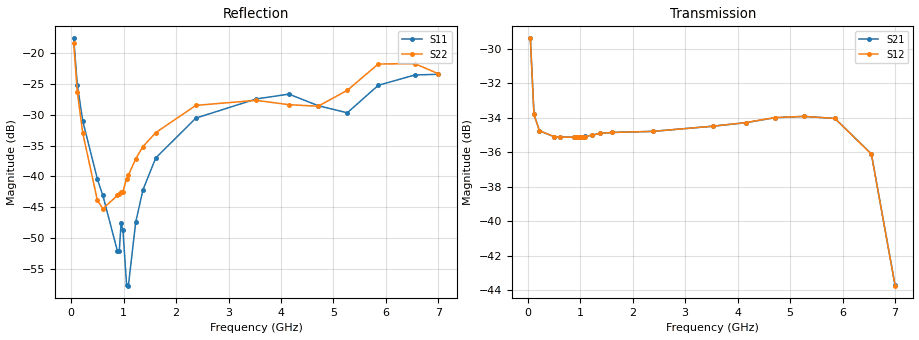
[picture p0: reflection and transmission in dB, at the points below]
! Integrated Device Technology
! Corporate Headquarters
! 6024 Silver Creek Valley Road
! San Jose, CA 95138  USA
! Phone:  1-408-284-8200
! Toll Free:  1-800-223-1366
! Webpage:  http://www.idt.com/
! Timing and RF Division
! 515 Groton Road, Suite 102
! Westford, MA 01886-6024
! Device:  F2258
! Description: Voltage Variable RF Attenuator
! Frequency:  50.0 -  6000.00 MHz
! Package:  3x3 mm Thin QFN Plastic Package: 16 pin
! Ports:  2 RF, 2 DC
!  Pin  1  = NC
!  Pin  2  = NC
!  Pin  3  = RF2  = Port 2
!  Pin  4  = GND
!  Pin  5  = Vdd
!  Pin  6  = NC
!  Pin  7  = VCTRL
!  Pin  8  = NC
!  Pin  9  = GND
!  Pin 10  = RF1  = Port 1
!  Pin 11  = NC
!  Pin 12  = NC
!  Pin 13  = NC
!  Pin 14  = NC
!  Pin 15  = NC
!  Pin 16  = NC
! Vcntrl:  2.050 Volts
! Vdd:  +3.300 Volts
! Current:  1.154 mA
! Data:  The device was measured on a the F2258 evaluation board which has
!  individual transmission lines to the RF pins.  Data was collected
!  using a calibrated network analyzer.  The evaluation board was
!  de-embedded using a TRL calibration technique.
!  The reference plane is the edge of the package pin.
! Misc:  SN 10
!  Action Tracker AT0285
! Date Measured:  2014-12-10
! Date:  2016-01-13  MJV
! Note:
!  Integrated Device Technology supplies this data as a sample of measured
!  data at the package pin for this product.  Your particular data for this
!  product may vary.
!  Data was taken at 25 degrees C.
!  Integrated Device Technology reserves the right to change this data at anytime.
!Freq_(GHz)  S11M_(dB)  S11P_(deg)  S21M_(dB)  S21P_(deg)  S12M_(dB)  S12P_(deg)  S22M_(dB)  S22P_(deg)
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# GHz S dB R 50
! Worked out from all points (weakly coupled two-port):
!   201 points, 50 MHz to 7 GHz, reference 50 ohm
!   highest |S21| = -29.40 dB at 50 MHz (marker M1); lowest = -43.7 dB at 7 GHz (marker M2)
!   lowest |S11| = -57.8 dB at 1.093 GHz (marker M3), VSWR 1.00, Z = 49.9 + j0.113 ohm
!   |S11| at or under -10 dB: start of sweep to end of sweep
!   |S22| runs from -45.3 to -18.3 dB; largest |S21 - S12| = 5.5e-05
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0.05  -17.55 -111.0  -29.40 -67.2  -29.40 -67.2  -18.28 -109.2
0.1195  -25.12 -106.8  -33.81 -36.1  -33.81 -36.1  -26.32 -98.0
0.22375  -31.02 -110.6  -34.75 -20.9  -34.76 -20.9  -32.98 -90.3
0.50175  -40.45 -121.6  -35.10 -11.2  -35.09 -11.2  -43.89 -41.5
0.606  -43.10 -125.7  -35.12 -10.0  -35.12 -10.0  -45.26 -10.5
0.884  -52.17 166.3  -35.13 -8.6  -35.13 -8.6  -43.09 34.2
0.91875  -52.11 150.2  -35.12 -8.5  -35.12 -8.5  -42.80 36.6
0.9535  -47.62 -162.9  -35.13 -8.4  -35.14 -8.4  -42.50 63.4
0.98825  -48.68 -174.1  -35.12 -8.3  -35.12 -8.3  -42.46 59.6
1.05775  -57.65 153.4  -35.10 -8.2  -35.10 -8.2  -40.40 50.7
1.0925  -57.78 119.0  -35.08 -8.2  -35.09 -8.1  -39.82 49.3
1.2315  -47.48 45.9  -35.01 -8.2  -35.01 -8.2  -37.15 39.7
1.3705  -42.17 36.7  -34.91 -8.7  -34.91 -8.7  -35.15 36.1
1.61375  -37.00 32.8  -34.85 -10.0  -34.85 -10.0  -32.88 30.9
2.37825  -30.52 48.1  -34.79 -13.7  -34.79 -13.7  -28.45 30.2
3.525  -27.41 91.6  -34.49 -20.4  -34.49 -20.4  -27.63 56.9
4.1505  -26.62 104.9  -34.29 -25.0  -34.28 -24.9  -28.34 66.5
4.7065  -28.49 95.6  -34.00 -29.6  -33.99 -29.7  -28.59 48.6
5.2625  -29.66 54.2  -33.92 -35.8  -33.92 -35.7  -26.01 11.6
5.85325  -25.19 29.8  -34.04 -46.3  -34.04 -46.2  -21.72 -8.4
6.54825  -23.51 45.0  -36.09 -66.6  -36.11 -66.6  -21.66 -42.5
7  -23.39 84.5  -43.71 -62.0  -43.73 -61.6  -23.30 -128.5
